VERSION 5.7 ;
  NOWIREEXTENSIONATPIN ON ;
  DIVIDERCHAR "/" ;
  BUSBITCHARS "[]" ;
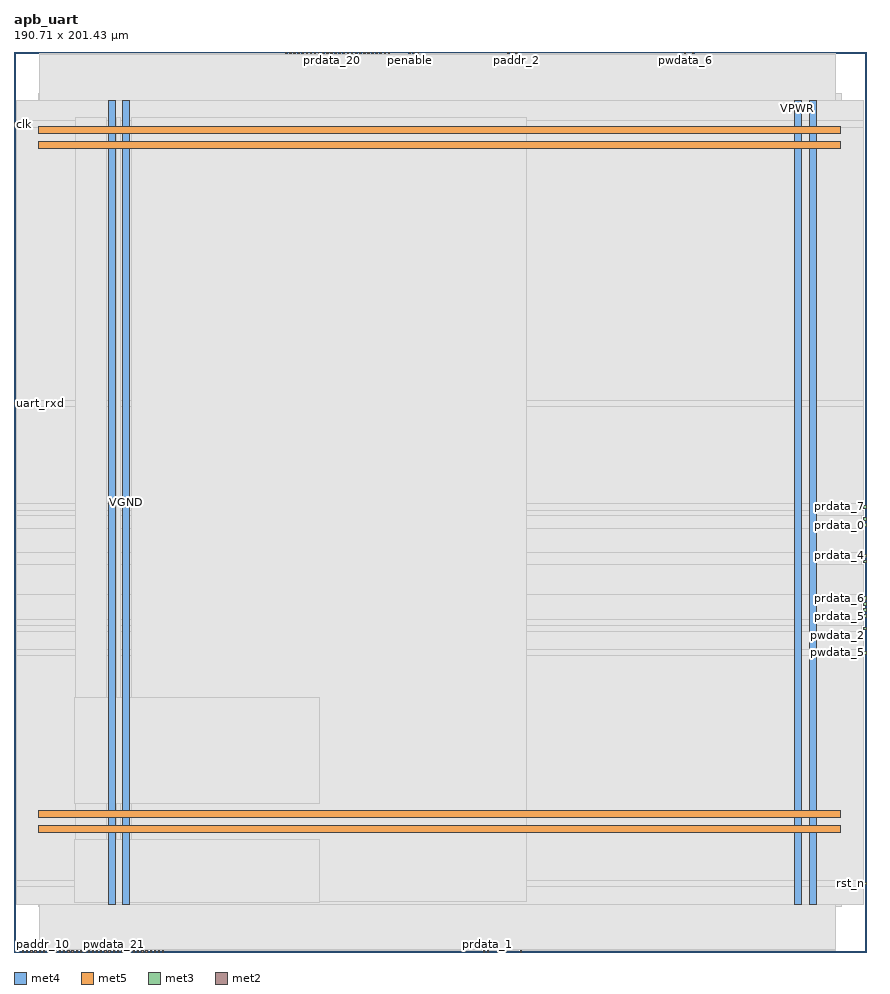
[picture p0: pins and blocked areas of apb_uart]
MACRO apb_uart
  CLASS BLOCK ;
  FOREIGN apb_uart ;
  ORIGIN 0.000 0.000 ;
  SIZE 190.710 BY 201.430 ;
  PIN VGND
    DIRECTION INOUT ;
    USE GROUND ;
    PORT
      LAYER met4 ;
        RECT 24.340 10.640 25.940 190.640 ;
    END
    PORT
      LAYER met4 ;
        RECT 177.940 10.640 179.540 190.640 ;
    END
    PORT
      LAYER met5 ;
        RECT 5.520 30.030 184.920 31.630 ;
    END
    PORT
      LAYER met5 ;
        RECT 5.520 183.210 184.920 184.810 ;
    END
  END VGND
  PIN VPWR
    DIRECTION INOUT ;
    USE POWER ;
    PORT
      LAYER met4 ;
        RECT 21.040 10.640 22.640 190.640 ;
    END
    PORT
      LAYER met4 ;
        RECT 174.640 10.640 176.240 190.640 ;
    END
    PORT
      LAYER met5 ;
        RECT 5.520 26.730 184.920 28.330 ;
    END
    PORT
      LAYER met5 ;
        RECT 5.520 179.910 184.920 181.510 ;
    END
  END VPWR
  PIN clk
    DIRECTION INPUT ;
    USE SIGNAL ;
    ANTENNAGATEAREA 1.286700 ;
    ANTENNADIFFAREA 0.434700 ;
    PORT
      LAYER met3 ;
        RECT 0.000 185.000 0.600 185.600 ;
    END
  END clk
  PIN irq
    DIRECTION OUTPUT ;
    USE SIGNAL ;
    PORT
      LAYER met2 ;
        RECT 1.930 0.000 2.210 0.280 ;
    END
  END irq
  PIN paddr_0
    DIRECTION INPUT ;
    USE SIGNAL ;
    PORT
      LAYER met2 ;
        RECT 2.850 0.000 3.130 0.280 ;
    END
  END paddr_0
  PIN paddr_1
    DIRECTION INPUT ;
    USE SIGNAL ;
    PORT
      LAYER met2 ;
        RECT 3.770 0.000 4.050 0.280 ;
    END
  END paddr_1
  PIN paddr_10
    DIRECTION INPUT ;
    USE SIGNAL ;
    PORT
      LAYER met2 ;
        RECT 4.690 0.000 4.970 0.280 ;
    END
  END paddr_10
  PIN paddr_11
    DIRECTION INPUT ;
    USE SIGNAL ;
    PORT
      LAYER met2 ;
        RECT 5.610 0.000 5.890 0.280 ;
    END
  END paddr_11
  PIN paddr_2
    DIRECTION INPUT ;
    USE SIGNAL ;
    ANTENNAGATEAREA 0.647700 ;
    ANTENNADIFFAREA 0.434700 ;
    PORT
      LAYER met2 ;
        RECT 112.330 201.150 112.610 201.430 ;
    END
  END paddr_2
  PIN paddr_3
    DIRECTION INPUT ;
    USE SIGNAL ;
    ANTENNAGATEAREA 0.647700 ;
    ANTENNADIFFAREA 0.434700 ;
    PORT
      LAYER met2 ;
        RECT 111.410 201.150 111.690 201.430 ;
    END
  END paddr_3
  PIN paddr_4
    DIRECTION INPUT ;
    USE SIGNAL ;
    ANTENNAGATEAREA 0.647700 ;
    ANTENNADIFFAREA 0.434700 ;
    PORT
      LAYER met2 ;
        RECT 110.490 201.150 110.770 201.430 ;
    END
  END paddr_4
  PIN paddr_5
    DIRECTION INPUT ;
    USE SIGNAL ;
    PORT
      LAYER met2 ;
        RECT 6.530 0.000 6.810 0.280 ;
    END
  END paddr_5
  PIN paddr_6
    DIRECTION INPUT ;
    USE SIGNAL ;
    PORT
      LAYER met2 ;
        RECT 7.450 0.000 7.730 0.280 ;
    END
  END paddr_6
  PIN paddr_7
    DIRECTION INPUT ;
    USE SIGNAL ;
    PORT
      LAYER met2 ;
        RECT 8.370 0.000 8.650 0.280 ;
    END
  END paddr_7
  PIN paddr_8
    DIRECTION INPUT ;
    USE SIGNAL ;
    PORT
      LAYER met2 ;
        RECT 9.290 0.000 9.570 0.280 ;
    END
  END paddr_8
  PIN paddr_9
    DIRECTION INPUT ;
    USE SIGNAL ;
    PORT
      LAYER met2 ;
        RECT 10.210 0.000 10.490 0.280 ;
    END
  END paddr_9
  PIN penable
    DIRECTION INPUT ;
    USE SIGNAL ;
    ANTENNAGATEAREA 0.647700 ;
    ANTENNADIFFAREA 0.434700 ;
    PORT
      LAYER met2 ;
        RECT 88.410 201.150 88.690 201.430 ;
    END
  END penable
  PIN prdata_0
    DIRECTION OUTPUT ;
    USE SIGNAL ;
    ANTENNAGATEAREA 0.434700 ;
    ANTENNADIFFAREA 1.137600 ;
    PORT
      LAYER met3 ;
        RECT 190.110 95.240 190.710 95.840 ;
    END
  END prdata_0
  PIN prdata_1
    DIRECTION OUTPUT ;
    USE SIGNAL ;
    ANTENNAGATEAREA 0.434700 ;
    ANTENNADIFFAREA 1.137600 ;
    PORT
      LAYER met2 ;
        RECT 105.890 0.000 106.170 0.280 ;
    END
  END prdata_1
  PIN prdata_10
    DIRECTION OUTPUT ;
    USE SIGNAL ;
    ANTENNAGATEAREA 0.434700 ;
    ANTENNADIFFAREA 0.775300 ;
    PORT
      LAYER met2 ;
        RECT 83.810 201.150 84.090 201.430 ;
    END
  END prdata_10
  PIN prdata_11
    DIRECTION OUTPUT ;
    USE SIGNAL ;
    ANTENNAGATEAREA 0.434700 ;
    ANTENNADIFFAREA 0.775300 ;
    PORT
      LAYER met2 ;
        RECT 82.890 201.150 83.170 201.430 ;
    END
  END prdata_11
  PIN prdata_12
    DIRECTION OUTPUT ;
    USE SIGNAL ;
    ANTENNAGATEAREA 0.434700 ;
    ANTENNADIFFAREA 0.775300 ;
    PORT
      LAYER met2 ;
        RECT 80.130 201.150 80.410 201.430 ;
    END
  END prdata_12
  PIN prdata_13
    DIRECTION OUTPUT ;
    USE SIGNAL ;
    ANTENNAGATEAREA 0.434700 ;
    ANTENNADIFFAREA 0.775300 ;
    PORT
      LAYER met2 ;
        RECT 60.810 201.150 61.090 201.430 ;
    END
  END prdata_13
  PIN prdata_14
    DIRECTION OUTPUT ;
    USE SIGNAL ;
    ANTENNAGATEAREA 0.434700 ;
    ANTENNADIFFAREA 0.775300 ;
    PORT
      LAYER met2 ;
        RECT 81.050 201.150 81.330 201.430 ;
    END
  END prdata_14
  PIN prdata_15
    DIRECTION OUTPUT ;
    USE SIGNAL ;
    ANTENNAGATEAREA 0.434700 ;
    ANTENNADIFFAREA 0.775300 ;
    PORT
      LAYER met2 ;
        RECT 71.850 201.150 72.130 201.430 ;
    END
  END prdata_15
  PIN prdata_16
    DIRECTION OUTPUT ;
    USE SIGNAL ;
    ANTENNAGATEAREA 0.434700 ;
    ANTENNADIFFAREA 0.775300 ;
    PORT
      LAYER met2 ;
        RECT 73.690 201.150 73.970 201.430 ;
    END
  END prdata_16
  PIN prdata_17
    DIRECTION OUTPUT ;
    USE SIGNAL ;
    ANTENNAGATEAREA 0.434700 ;
    ANTENNADIFFAREA 0.775300 ;
    PORT
      LAYER met2 ;
        RECT 67.250 201.150 67.530 201.430 ;
    END
  END prdata_17
  PIN prdata_18
    DIRECTION OUTPUT ;
    USE SIGNAL ;
    ANTENNAGATEAREA 0.434700 ;
    ANTENNADIFFAREA 0.775300 ;
    PORT
      LAYER met2 ;
        RECT 66.330 201.150 66.610 201.430 ;
    END
  END prdata_18
  PIN prdata_19
    DIRECTION OUTPUT ;
    USE SIGNAL ;
    ANTENNAGATEAREA 0.434700 ;
    ANTENNADIFFAREA 0.775300 ;
    PORT
      LAYER met2 ;
        RECT 77.370 201.150 77.650 201.430 ;
    END
  END prdata_19
  PIN prdata_2
    DIRECTION OUTPUT ;
    USE SIGNAL ;
    ANTENNAGATEAREA 0.434700 ;
    ANTENNADIFFAREA 1.137600 ;
    PORT
      LAYER met2 ;
        RECT 113.250 0.000 113.530 0.280 ;
    END
  END prdata_2
  PIN prdata_20
    DIRECTION OUTPUT ;
    USE SIGNAL ;
    ANTENNAGATEAREA 0.434700 ;
    ANTENNADIFFAREA 0.775300 ;
    PORT
      LAYER met2 ;
        RECT 70.930 201.150 71.210 201.430 ;
    END
  END prdata_20
  PIN prdata_21
    DIRECTION OUTPUT ;
    USE SIGNAL ;
    ANTENNAGATEAREA 0.434700 ;
    ANTENNADIFFAREA 0.775300 ;
    PORT
      LAYER met2 ;
        RECT 74.610 201.150 74.890 201.430 ;
    END
  END prdata_21
  PIN prdata_22
    DIRECTION OUTPUT ;
    USE SIGNAL ;
    ANTENNAGATEAREA 0.434700 ;
    ANTENNADIFFAREA 0.775300 ;
    PORT
      LAYER met2 ;
        RECT 72.770 201.150 73.050 201.430 ;
    END
  END prdata_22
  PIN prdata_23
    DIRECTION OUTPUT ;
    USE SIGNAL ;
    ANTENNAGATEAREA 0.434700 ;
    ANTENNADIFFAREA 0.775300 ;
    PORT
      LAYER met2 ;
        RECT 81.970 201.150 82.250 201.430 ;
    END
  END prdata_23
  PIN prdata_24
    DIRECTION OUTPUT ;
    USE SIGNAL ;
    ANTENNAGATEAREA 0.434700 ;
    ANTENNADIFFAREA 0.775300 ;
    PORT
      LAYER met2 ;
        RECT 76.450 201.150 76.730 201.430 ;
    END
  END prdata_24
  PIN prdata_25
    DIRECTION OUTPUT ;
    USE SIGNAL ;
    ANTENNAGATEAREA 0.434700 ;
    ANTENNADIFFAREA 0.775300 ;
    PORT
      LAYER met2 ;
        RECT 63.570 201.150 63.850 201.430 ;
    END
  END prdata_25
  PIN prdata_26
    DIRECTION OUTPUT ;
    USE SIGNAL ;
    ANTENNAGATEAREA 0.434700 ;
    ANTENNADIFFAREA 0.775300 ;
    PORT
      LAYER met2 ;
        RECT 62.650 201.150 62.930 201.430 ;
    END
  END prdata_26
  PIN prdata_27
    DIRECTION OUTPUT ;
    USE SIGNAL ;
    ANTENNAGATEAREA 0.434700 ;
    ANTENNADIFFAREA 0.775300 ;
    PORT
      LAYER met2 ;
        RECT 69.090 201.150 69.370 201.430 ;
    END
  END prdata_27
  PIN prdata_28
    DIRECTION OUTPUT ;
    USE SIGNAL ;
    ANTENNAGATEAREA 0.434700 ;
    ANTENNADIFFAREA 0.775300 ;
    PORT
      LAYER met2 ;
        RECT 79.210 201.150 79.490 201.430 ;
    END
  END prdata_28
  PIN prdata_29
    DIRECTION OUTPUT ;
    USE SIGNAL ;
    ANTENNAGATEAREA 0.434700 ;
    ANTENNADIFFAREA 0.775300 ;
    PORT
      LAYER met2 ;
        RECT 70.010 201.150 70.290 201.430 ;
    END
  END prdata_29
  PIN prdata_3
    DIRECTION OUTPUT ;
    USE SIGNAL ;
    ANTENNAGATEAREA 0.434700 ;
    ANTENNADIFFAREA 1.137600 ;
    PORT
      LAYER met2 ;
        RECT 104.970 0.000 105.250 0.280 ;
    END
  END prdata_3
  PIN prdata_30
    DIRECTION OUTPUT ;
    USE SIGNAL ;
    ANTENNAGATEAREA 0.434700 ;
    ANTENNADIFFAREA 0.775300 ;
    PORT
      LAYER met2 ;
        RECT 78.290 201.150 78.570 201.430 ;
    END
  END prdata_30
  PIN prdata_31
    DIRECTION OUTPUT ;
    USE SIGNAL ;
    ANTENNAGATEAREA 0.434700 ;
    ANTENNADIFFAREA 0.775300 ;
    PORT
      LAYER met2 ;
        RECT 65.410 201.150 65.690 201.430 ;
    END
  END prdata_31
  PIN prdata_4
    DIRECTION OUTPUT ;
    USE SIGNAL ;
    ANTENNAGATEAREA 0.560700 ;
    ANTENNADIFFAREA 0.863700 ;
    PORT
      LAYER met3 ;
        RECT 190.110 88.440 190.710 89.040 ;
    END
  END prdata_4
  PIN prdata_5
    DIRECTION OUTPUT ;
    USE SIGNAL ;
    ANTENNAGATEAREA 0.560700 ;
    ANTENNADIFFAREA 0.863700 ;
    PORT
      LAYER met3 ;
        RECT 190.110 74.840 190.710 75.440 ;
    END
  END prdata_5
  PIN prdata_6
    DIRECTION OUTPUT ;
    USE SIGNAL ;
    ANTENNAGATEAREA 0.560700 ;
    ANTENNADIFFAREA 0.863700 ;
    PORT
      LAYER met3 ;
        RECT 190.110 78.920 190.710 79.520 ;
    END
  END prdata_6
  PIN prdata_7
    DIRECTION OUTPUT ;
    USE SIGNAL ;
    ANTENNAGATEAREA 0.434700 ;
    ANTENNADIFFAREA 1.137600 ;
    PORT
      LAYER met3 ;
        RECT 190.110 99.320 190.710 99.920 ;
    END
  END prdata_7
  PIN prdata_8
    DIRECTION OUTPUT ;
    USE SIGNAL ;
    ANTENNAGATEAREA 0.434700 ;
    ANTENNADIFFAREA 0.434700 ;
    PORT
      LAYER met2 ;
        RECT 64.490 201.150 64.770 201.430 ;
    END
  END prdata_8
  PIN prdata_9
    DIRECTION OUTPUT ;
    USE SIGNAL ;
    ANTENNAGATEAREA 0.434700 ;
    ANTENNADIFFAREA 0.775300 ;
    PORT
      LAYER met2 ;
        RECT 68.170 201.150 68.450 201.430 ;
    END
  END prdata_9
  PIN pready
    DIRECTION OUTPUT ;
    USE SIGNAL ;
    PORT
      LAYER met2 ;
        RECT 11.130 0.000 11.410 0.280 ;
    END
  END pready
  PIN psel
    DIRECTION INPUT ;
    USE SIGNAL ;
    ANTENNAGATEAREA 0.647700 ;
    ANTENNADIFFAREA 0.434700 ;
    PORT
      LAYER met2 ;
        RECT 89.330 201.150 89.610 201.430 ;
    END
  END psel
  PIN pslverr
    DIRECTION OUTPUT ;
    USE SIGNAL ;
    ANTENNAGATEAREA 0.434700 ;
    ANTENNADIFFAREA 0.775300 ;
    PORT
      LAYER met2 ;
        RECT 61.730 201.150 62.010 201.430 ;
    END
  END pslverr
  PIN pwdata_0
    DIRECTION INPUT ;
    USE SIGNAL ;
    ANTENNAGATEAREA 0.647700 ;
    ANTENNADIFFAREA 0.434700 ;
    PORT
      LAYER met3 ;
        RECT 190.110 96.600 190.710 97.200 ;
    END
  END pwdata_0
  PIN pwdata_1
    DIRECTION INPUT ;
    USE SIGNAL ;
    ANTENNAGATEAREA 0.647700 ;
    ANTENNADIFFAREA 0.434700 ;
    PORT
      LAYER met3 ;
        RECT 190.110 77.560 190.710 78.160 ;
    END
  END pwdata_1
  PIN pwdata_10
    DIRECTION INPUT ;
    USE SIGNAL ;
    PORT
      LAYER met2 ;
        RECT 12.050 0.000 12.330 0.280 ;
    END
  END pwdata_10
  PIN pwdata_11
    DIRECTION INPUT ;
    USE SIGNAL ;
    PORT
      LAYER met2 ;
        RECT 12.970 0.000 13.250 0.280 ;
    END
  END pwdata_11
  PIN pwdata_12
    DIRECTION INPUT ;
    USE SIGNAL ;
    PORT
      LAYER met2 ;
        RECT 13.890 0.000 14.170 0.280 ;
    END
  END pwdata_12
  PIN pwdata_13
    DIRECTION INPUT ;
    USE SIGNAL ;
    PORT
      LAYER met2 ;
        RECT 14.810 0.000 15.090 0.280 ;
    END
  END pwdata_13
  PIN pwdata_14
    DIRECTION INPUT ;
    USE SIGNAL ;
    PORT
      LAYER met2 ;
        RECT 15.730 0.000 16.010 0.280 ;
    END
  END pwdata_14
  PIN pwdata_15
    DIRECTION INPUT ;
    USE SIGNAL ;
    PORT
      LAYER met2 ;
        RECT 16.650 0.000 16.930 0.280 ;
    END
  END pwdata_15
  PIN pwdata_16
    DIRECTION INPUT ;
    USE SIGNAL ;
    PORT
      LAYER met2 ;
        RECT 17.570 0.000 17.850 0.280 ;
    END
  END pwdata_16
  PIN pwdata_17
    DIRECTION INPUT ;
    USE SIGNAL ;
    PORT
      LAYER met2 ;
        RECT 18.490 0.000 18.770 0.280 ;
    END
  END pwdata_17
  PIN pwdata_18
    DIRECTION INPUT ;
    USE SIGNAL ;
    PORT
      LAYER met2 ;
        RECT 19.410 0.000 19.690 0.280 ;
    END
  END pwdata_18
  PIN pwdata_19
    DIRECTION INPUT ;
    USE SIGNAL ;
    PORT
      LAYER met2 ;
        RECT 20.330 0.000 20.610 0.280 ;
    END
  END pwdata_19
  PIN pwdata_2
    DIRECTION INPUT ;
    USE SIGNAL ;
    ANTENNAGATEAREA 0.647700 ;
    ANTENNADIFFAREA 0.434700 ;
    PORT
      LAYER met3 ;
        RECT 190.110 72.120 190.710 72.720 ;
    END
  END pwdata_2
  PIN pwdata_20
    DIRECTION INPUT ;
    USE SIGNAL ;
    PORT
      LAYER met2 ;
        RECT 21.250 0.000 21.530 0.280 ;
    END
  END pwdata_20
  PIN pwdata_21
    DIRECTION INPUT ;
    USE SIGNAL ;
    PORT
      LAYER met2 ;
        RECT 22.170 0.000 22.450 0.280 ;
    END
  END pwdata_21
  PIN pwdata_22
    DIRECTION INPUT ;
    USE SIGNAL ;
    PORT
      LAYER met2 ;
        RECT 23.090 0.000 23.370 0.280 ;
    END
  END pwdata_22
  PIN pwdata_23
    DIRECTION INPUT ;
    USE SIGNAL ;
    PORT
      LAYER met2 ;
        RECT 24.010 0.000 24.290 0.280 ;
    END
  END pwdata_23
  PIN pwdata_24
    DIRECTION INPUT ;
    USE SIGNAL ;
    PORT
      LAYER met2 ;
        RECT 24.930 0.000 25.210 0.280 ;
    END
  END pwdata_24
  PIN pwdata_25
    DIRECTION INPUT ;
    USE SIGNAL ;
    PORT
      LAYER met2 ;
        RECT 25.850 0.000 26.130 0.280 ;
    END
  END pwdata_25
  PIN pwdata_26
    DIRECTION INPUT ;
    USE SIGNAL ;
    PORT
      LAYER met2 ;
        RECT 26.770 0.000 27.050 0.280 ;
    END
  END pwdata_26
  PIN pwdata_27
    DIRECTION INPUT ;
    USE SIGNAL ;
    PORT
      LAYER met2 ;
        RECT 27.690 0.000 27.970 0.280 ;
    END
  END pwdata_27
  PIN pwdata_28
    DIRECTION INPUT ;
    USE SIGNAL ;
    PORT
      LAYER met2 ;
        RECT 28.610 0.000 28.890 0.280 ;
    END
  END pwdata_28
  PIN pwdata_29
    DIRECTION INPUT ;
    USE SIGNAL ;
    PORT
      LAYER met2 ;
        RECT 29.530 0.000 29.810 0.280 ;
    END
  END pwdata_29
  PIN pwdata_3
    DIRECTION INPUT ;
    USE SIGNAL ;
    ANTENNAGATEAREA 0.647700 ;
    ANTENNADIFFAREA 0.434700 ;
    PORT
      LAYER met3 ;
        RECT 190.110 87.080 190.710 87.680 ;
    END
  END pwdata_3
  PIN pwdata_30
    DIRECTION INPUT ;
    USE SIGNAL ;
    PORT
      LAYER met2 ;
        RECT 30.450 0.000 30.730 0.280 ;
    END
  END pwdata_30
  PIN pwdata_31
    DIRECTION INPUT ;
    USE SIGNAL ;
    PORT
      LAYER met2 ;
        RECT 31.370 0.000 31.650 0.280 ;
    END
  END pwdata_31
  PIN pwdata_4
    DIRECTION INPUT ;
    USE SIGNAL ;
    ANTENNAGATEAREA 0.647700 ;
    ANTENNADIFFAREA 0.434700 ;
    PORT
      LAYER met3 ;
        RECT 190.110 76.200 190.710 76.800 ;
    END
  END pwdata_4
  PIN pwdata_5
    DIRECTION INPUT ;
    USE SIGNAL ;
    ANTENNAGATEAREA 0.647700 ;
    ANTENNADIFFAREA 0.434700 ;
    PORT
      LAYER met3 ;
        RECT 190.110 66.680 190.710 67.280 ;
    END
  END pwdata_5
  PIN pwdata_6
    DIRECTION INPUT ;
    USE SIGNAL ;
    ANTENNAGATEAREA 0.647700 ;
    ANTENNADIFFAREA 0.434700 ;
    PORT
      LAYER met2 ;
        RECT 150.050 201.150 150.330 201.430 ;
    END
  END pwdata_6
  PIN pwdata_7
    DIRECTION INPUT ;
    USE SIGNAL ;
    ANTENNAGATEAREA 0.647700 ;
    ANTENNADIFFAREA 0.434700 ;
    PORT
      LAYER met2 ;
        RECT 151.890 201.150 152.170 201.430 ;
    END
  END pwdata_7
  PIN pwdata_8
    DIRECTION INPUT ;
    USE SIGNAL ;
    PORT
      LAYER met2 ;
        RECT 32.290 0.000 32.570 0.280 ;
    END
  END pwdata_8
  PIN pwdata_9
    DIRECTION INPUT ;
    USE SIGNAL ;
    PORT
      LAYER met2 ;
        RECT 33.210 0.000 33.490 0.280 ;
    END
  END pwdata_9
  PIN pwrite
    DIRECTION INPUT ;
    USE SIGNAL ;
    ANTENNAGATEAREA 0.647700 ;
    ANTENNADIFFAREA 0.434700 ;
    PORT
      LAYER met2 ;
        RECT 90.250 201.150 90.530 201.430 ;
    END
  END pwrite
  PIN rst_n
    DIRECTION INPUT ;
    USE SIGNAL ;
    ANTENNAGATEAREA 0.647700 ;
    ANTENNADIFFAREA 0.434700 ;
    PORT
      LAYER met3 ;
        RECT 190.110 15.000 190.710 15.600 ;
    END
  END rst_n
  PIN uart_rxd
    DIRECTION INPUT ;
    USE SIGNAL ;
    ANTENNAGATEAREA 0.647700 ;
    ANTENNADIFFAREA 0.434700 ;
    PORT
      LAYER met3 ;
        RECT 0.000 122.440 0.600 123.040 ;
    END
  END uart_rxd
  PIN uart_txd
    DIRECTION OUTPUT ;
    USE SIGNAL ;
    ANTENNAGATEAREA 0.434700 ;
    ANTENNADIFFAREA 1.137600 ;
    PORT
      LAYER met2 ;
        RECT 75.530 201.150 75.810 201.430 ;
    END
  END uart_txd
  OBS
      LAYER nwell ;
        RECT 5.330 10.795 185.110 190.485 ;
      LAYER li1 ;
        RECT 5.520 10.795 184.920 190.485 ;
      LAYER met1 ;
        RECT 5.520 10.240 185.220 192.060 ;
      LAYER met2 ;
        RECT 5.610 200.870 60.530 201.150 ;
        RECT 61.370 200.870 61.450 201.150 ;
        RECT 62.290 200.870 62.370 201.150 ;
        RECT 63.210 200.870 63.290 201.150 ;
        RECT 64.130 200.870 64.210 201.150 ;
        RECT 65.050 200.870 65.130 201.150 ;
        RECT 65.970 200.870 66.050 201.150 ;
        RECT 66.890 200.870 66.970 201.150 ;
        RECT 67.810 200.870 67.890 201.150 ;
        RECT 68.730 200.870 68.810 201.150 ;
        RECT 69.650 200.870 69.730 201.150 ;
        RECT 70.570 200.870 70.650 201.150 ;
        RECT 71.490 200.870 71.570 201.150 ;
        RECT 72.410 200.870 72.490 201.150 ;
        RECT 73.330 200.870 73.410 201.150 ;
        RECT 74.250 200.870 74.330 201.150 ;
        RECT 75.170 200.870 75.250 201.150 ;
        RECT 76.090 200.870 76.170 201.150 ;
        RECT 77.010 200.870 77.090 201.150 ;
        RECT 77.930 200.870 78.010 201.150 ;
        RECT 78.850 200.870 78.930 201.150 ;
        RECT 79.770 200.870 79.850 201.150 ;
        RECT 80.690 200.870 80.770 201.150 ;
        RECT 81.610 200.870 81.690 201.150 ;
        RECT 82.530 200.870 82.610 201.150 ;
        RECT 83.450 200.870 83.530 201.150 ;
        RECT 84.370 200.870 88.130 201.150 ;
        RECT 88.970 200.870 89.050 201.150 ;
        RECT 89.890 200.870 89.970 201.150 ;
        RECT 90.810 200.870 110.210 201.150 ;
        RECT 111.050 200.870 111.130 201.150 ;
        RECT 111.970 200.870 112.050 201.150 ;
        RECT 112.890 200.870 149.770 201.150 ;
        RECT 150.610 200.870 151.610 201.150 ;
        RECT 152.450 200.870 183.910 201.150 ;
        RECT 5.610 0.560 183.910 200.870 ;
        RECT 6.170 0.280 6.250 0.560 ;
        RECT 7.090 0.280 7.170 0.560 ;
        RECT 8.010 0.280 8.090 0.560 ;
        RECT 8.930 0.280 9.010 0.560 ;
        RECT 9.850 0.280 9.930 0.560 ;
        RECT 10.770 0.280 10.850 0.560 ;
        RECT 11.690 0.280 11.770 0.560 ;
        RECT 12.610 0.280 12.690 0.560 ;
        RECT 13.530 0.280 13.610 0.560 ;
        RECT 14.450 0.280 14.530 0.560 ;
        RECT 15.370 0.280 15.450 0.560 ;
        RECT 16.290 0.280 16.370 0.560 ;
        RECT 17.210 0.280 17.290 0.560 ;
        RECT 18.130 0.280 18.210 0.560 ;
        RECT 19.050 0.280 19.130 0.560 ;
        RECT 19.970 0.280 20.050 0.560 ;
        RECT 20.890 0.280 20.970 0.560 ;
        RECT 21.810 0.280 21.890 0.560 ;
        RECT 22.730 0.280 22.810 0.560 ;
        RECT 23.650 0.280 23.730 0.560 ;
        RECT 24.570 0.280 24.650 0.560 ;
        RECT 25.490 0.280 25.570 0.560 ;
        RECT 26.410 0.280 26.490 0.560 ;
        RECT 27.330 0.280 27.410 0.560 ;
        RECT 28.250 0.280 28.330 0.560 ;
        RECT 29.170 0.280 29.250 0.560 ;
        RECT 30.090 0.280 30.170 0.560 ;
        RECT 31.010 0.280 31.090 0.560 ;
        RECT 31.930 0.280 32.010 0.560 ;
        RECT 32.850 0.280 32.930 0.560 ;
        RECT 33.770 0.280 104.690 0.560 ;
        RECT 105.530 0.280 105.610 0.560 ;
        RECT 106.450 0.280 112.970 0.560 ;
        RECT 113.810 0.280 183.910 0.560 ;
      LAYER met3 ;
        RECT 0.600 186.000 190.110 190.565 ;
        RECT 1.000 184.600 190.110 186.000 ;
        RECT 0.600 123.440 190.110 184.600 ;
        RECT 1.000 122.040 190.110 123.440 ;
        RECT 0.600 100.320 190.110 122.040 ;
        RECT 0.600 98.920 189.710 100.320 ;
        RECT 0.600 97.600 190.110 98.920 ;
        RECT 0.600 94.840 189.710 97.600 ;
        RECT 0.600 89.440 190.110 94.840 ;
        RECT 0.600 86.680 189.710 89.440 ;
        RECT 0.600 79.920 190.110 86.680 ;
        RECT 0.600 74.440 189.710 79.920 ;
        RECT 0.600 73.120 190.110 74.440 ;
        RECT 0.600 71.720 189.710 73.120 ;
        RECT 0.600 67.680 190.110 71.720 ;
        RECT 0.600 66.280 189.710 67.680 ;
        RECT 0.600 16.000 190.110 66.280 ;
        RECT 0.600 14.600 189.710 16.000 ;
        RECT 0.600 10.715 190.110 14.600 ;
      LAYER met4 ;
        RECT 13.670 11.310 20.640 186.825 ;
        RECT 23.040 11.310 23.940 186.825 ;
        RECT 26.340 11.310 114.705 186.825 ;
      LAYER met5 ;
        RECT 13.460 33.230 68.420 56.900 ;
        RECT 13.460 11.100 68.420 25.130 ;
  END
END apb_uart
END LIBRARY

